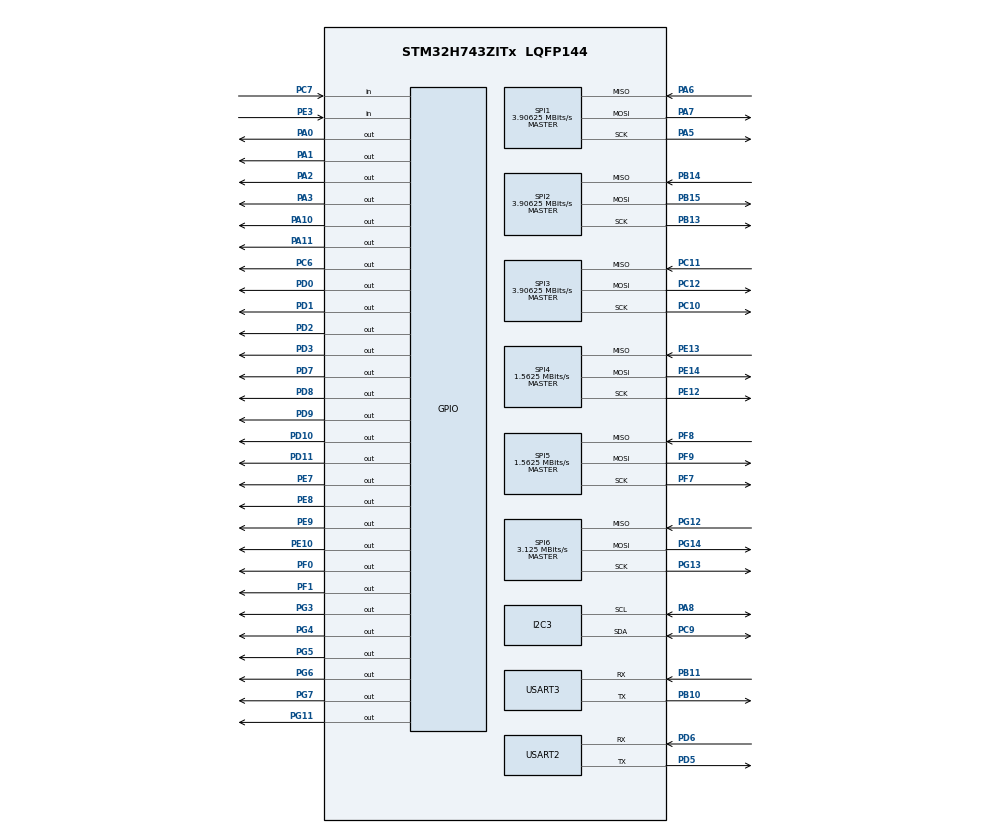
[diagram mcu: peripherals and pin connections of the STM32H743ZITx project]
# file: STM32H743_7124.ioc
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I2C3.Timing=0x00606092
Mcu.Family=STM32H7
Mcu.Name=STM32H743ZITx
Mcu.Package=LQFP144
NVIC.PriorityGroup=NVIC_PRIORITYGROUP_4
NVIC.TIM1_UP_IRQn=true\:0\:0\:false\:false\:true\:true\:true\:true
NVIC.TIM2_IRQn=true\:0\:0\:false\:false\:true\:true\:true\:true
NVIC.TIM3_IRQn=true\:0\:0\:false\:false\:true\:true\:true\:true
PA0.Signal=GPIO_Output
PA1.Signal=GPIO_Output
PA10.Signal=GPIO_Output
PA11.Signal=GPIO_Output
PA2.Signal=GPIO_Output
PA3.Signal=GPIO_Output
PA5.Mode=Full_Duplex_Master
PA5.Signal=SPI1_SCK
PA6.Mode=Full_Duplex_Master
PA6.Signal=SPI1_MISO
PA7.Mode=Full_Duplex_Master
PA7.Signal=SPI1_MOSI
PA8.Mode=I2C
PA8.Signal=I2C3_SCL
PB10.Mode=Asynchronous
PB10.Signal=USART3_TX
PB11.Mode=Asynchronous
PB11.Signal=USART3_RX
PB13.Mode=Full_Duplex_Master
PB13.Signal=SPI2_SCK
PB14.Mode=Full_Duplex_Master
PB14.Signal=SPI2_MISO
PB15.Mode=Full_Duplex_Master
PB15.Signal=SPI2_MOSI
PC10.Mode=Full_Duplex_Master
PC10.Signal=SPI3_SCK
PC11.Mode=Full_Duplex_Master
PC11.Signal=SPI3_MISO
PC12.Mode=Full_Duplex_Master
PC12.Signal=SPI3_MOSI
PC6.Signal=GPIO_Output
PC7.Signal=GPIO_Input
PC9.Mode=I2C
PC9.Signal=I2C3_SDA
PD0.Signal=GPIO_Output
PD1.Signal=GPIO_Output
PD10.Signal=GPIO_Output
PD11.Signal=GPIO_Output
PD2.Signal=GPIO_Output
PD3.Signal=GPIO_Output
PD5.Mode=Asynchronous
PD5.Signal=USART2_TX
PD6.Mode=Asynchronous
PD6.Signal=USART2_RX
PD7.Signal=GPIO_Output
PD8.Signal=GPIO_Output
PD9.Signal=GPIO_Output
PE10.Signal=GPIO_Output
PE12.Mode=Full_Duplex_Master
PE12.Signal=SPI4_SCK
PE13.Mode=Full_Duplex_Master
PE13.Signal=SPI4_MISO
PE14.Mode=Full_Duplex_Master
PE14.Signal=SPI4_MOSI
PE3.Signal=GPIO_Input
PE7.Signal=GPIO_Output
PE8.Signal=GPIO_Output
PE9.Signal=GPIO_Output
PF0.Signal=GPIO_Output
PF1.Signal=GPIO_Output
PF7.Mode=Full_Duplex_Master
PF7.Signal=SPI5_SCK
PF8.Mode=Full_Duplex_Master
PF8.Signal=SPI5_MISO
PF9.Mode=Full_Duplex_Master
PF9.Signal=SPI5_MOSI
PG11.Signal=GPIO_Output
PG12.Mode=Full_Duplex_Master
PG12.Signal=SPI6_MISO
PG13.Mode=Full_Duplex_Master
PG13.Signal=SPI6_SCK
PG14.Mode=Full_Duplex_Master
PG14.Signal=SPI6_MOSI
PG3.Signal=GPIO_Output
PG4.Signal=GPIO_Output
PG5.Signal=GPIO_Output
PG6.Signal=GPIO_Output
PG7.Signal=GPIO_Output
PH0-OSC_IN\ (PH0).Mode=HSE-External-Oscillator
PH0-OSC_IN\ (PH0).Signal=RCC_OSC_IN
PH1-OSC_OUT\ (PH1).Mode=HSE-External-Oscillator
PH1-OSC_OUT\ (PH1).Signal=RCC_OSC_OUT
ProjectManager.HeapSize=0x200
ProjectManager.StackSize=0x400
ProjectManager.TargetToolchain=MDK-ARM V5.27
RCC.ADCFreq_Value=62500000
RCC.APB1Freq_Value=25000000
RCC.APB2Freq_Value=25000000
RCC.APB3Freq_Value=50000000
RCC.APB4Freq_Value=50000000
RCC.CortexFreq_Value=400000000
RCC.D1PPRE=RCC_APB3_DIV2
RCC.D2PPRE1=RCC_APB1_DIV4
RCC.D2PPRE2=RCC_APB2_DIV4
RCC.D3PPRE=RCC_APB4_DIV2
RCC.DIVM1=2
RCC.DIVM2=2
RCC.DIVM3=2
RCC.DIVN1=64
RCC.DIVN2=50
RCC.DIVN3=50
RCC.DIVP2=10
RCC.HCLKFreq_Value=100000000
RCC.HPRE=RCC_HCLK_DIV4
RCC.HSE_VALUE=25000000
RCC.PLL1_VCI_Range-AdvancedSettings=RCC_PLL1VCIRANGE_1
RCC.PLL2_VCI_Range-AdvancedSettings=RCC_PLL2VCIRANGE_0
RCC.PLL2_VCO_SEL-AdvancedSettings=RCC_PLL2VCOMEDIUM
RCC.PLL3_VCI_Range-AdvancedSettings=RCC_PLL3VCIRANGE_0
RCC.PLLFRACN=0
RCC.PLLSourceVirtual=RCC_PLLSOURCE_HSE
RCC.SPI123CLockSelection=RCC_SPI123CLKSOURCE_PLL2
RCC.SYSCLKFreq_VALUE=400000000
RCC.SYSCLKSource=RCC_SYSCLKSOURCE_PLLCLK
RCC.USBFreq_Value=400000000
SPI1.BaudRatePrescaler=SPI_BAUDRATEPRESCALER_16
SPI1.CLKPhase=SPI_PHASE_2EDGE
SPI1.CLKPolarity=SPI_POLARITY_HIGH
SPI1.CalculateBaudRate=3.90625 MBits/s
SPI1.DataSize=SPI_DATASIZE_8BIT
SPI1.Direction=SPI_DIRECTION_2LINES
SPI1.Mode=SPI_MODE_MASTER
SPI1.NSSPMode=SPI_NSS_PULSE_DISABLE
SPI1.VirtualType=VM_MASTER
SPI2.BaudRatePrescaler=SPI_BAUDRATEPRESCALER_16
SPI2.CLKPhase=SPI_PHASE_2EDGE
SPI2.CLKPolarity=SPI_POLARITY_HIGH
SPI2.CalculateBaudRate=3.90625 MBits/s
SPI2.DataSize=SPI_DATASIZE_8BIT
SPI2.Direction=SPI_DIRECTION_2LINES
SPI2.Mode=SPI_MODE_MASTER
SPI2.NSSPMode=SPI_NSS_PULSE_DISABLE
SPI2.VirtualType=VM_MASTER
SPI3.BaudRatePrescaler=SPI_BAUDRATEPRESCALER_16
SPI3.CLKPhase=SPI_PHASE_2EDGE
SPI3.CLKPolarity=SPI_POLARITY_HIGH
SPI3.CalculateBaudRate=3.90625 MBits/s
SPI3.DataSize=SPI_DATASIZE_8BIT
SPI3.Direction=SPI_DIRECTION_2LINES
SPI3.Mode=SPI_MODE_MASTER
SPI3.NSSPMode=SPI_NSS_PULSE_DISABLE
SPI3.VirtualType=VM_MASTER
SPI4.BaudRatePrescaler=SPI_BAUDRATEPRESCALER_16
SPI4.CLKPhase=SPI_PHASE_2EDGE
SPI4.CLKPolarity=SPI_POLARITY_HIGH
SPI4.CalculateBaudRate=1.5625 MBits/s
SPI4.DataSize=SPI_DATASIZE_8BIT
SPI4.Direction=SPI_DIRECTION_2LINES
SPI4.Mode=SPI_MODE_MASTER
SPI4.NSSPMode=SPI_NSS_PULSE_DISABLE
SPI4.VirtualType=VM_MASTER
SPI5.BaudRatePrescaler=SPI_BAUDRATEPRESCALER_16
SPI5.CLKPhase=SPI_PHASE_2EDGE
SPI5.CLKPolarity=SPI_POLARITY_HIGH
SPI5.CalculateBaudRate=1.5625 MBits/s
SPI5.DataSize=SPI_DATASIZE_8BIT
SPI5.Direction=SPI_DIRECTION_2LINES
SPI5.Mode=SPI_MODE_MASTER
SPI5.NSSPMode=SPI_NSS_PULSE_DISABLE
SPI5.VirtualType=VM_MASTER
SPI6.BaudRatePrescaler=SPI_BAUDRATEPRESCALER_16
SPI6.CalculateBaudRate=3.125 MBits/s
SPI6.DataSize=SPI_DATASIZE_8BIT
SPI6.Direction=SPI_DIRECTION_2LINES
SPI6.Mode=SPI_MODE_MASTER
SPI6.NSSPMode=SPI_NSS_PULSE_DISABLE
SPI6.VirtualType=VM_MASTER
TIM1.Period=1000
TIM1.Prescaler=479
TIM2.Period=1000
TIM2.Prescaler=479
TIM3.Period=1000
TIM3.Prescaler=479
USART2.VirtualMode-Asynchronous=VM_ASYNC
USART3.VirtualMode-Asynchronous=VM_ASYNC
VP_TIM1_VS_ClockSourceINT.Mode=Internal
VP_TIM2_VS_ClockSourceINT.Mode=Internal
VP_TIM3_VS_ClockSourceINT.Mode=Internal
board=custom

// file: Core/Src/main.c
/* USER CODE BEGIN Header */
/**
  ******************************************************************************
  * @file           : main.c
  * @brief          : Main program body
  ******************************************************************************
  * @attention
  *
  * Copyright (c) 2022 STMicroelectronics.
  * All rights reserved.
  *
  * This software is licensed under terms that can be found in the LICENSE file
  * in the root directory of this software component.
  * If no LICENSE file comes with this software, it is provided AS-IS.
  *
  ******************************************************************************
  */
/* USER CODE END Header */
#include "main.h"

/* USER CODE BEGIN PM */
uint8_t TIMER_to_scan_Cnt;
uint8_t AD_scan_index=0;
int AD1_DATA[5],AD2_DATA[5],AD3_DATA[5],AD4_DATA[5],average_int=0;
/* USER CODE END PM */

I2C_HandleTypeDef hi2c3;

SPI_HandleTypeDef hspi1;
SPI_HandleTypeDef hspi2;
SPI_HandleTypeDef hspi3;
SPI_HandleTypeDef hspi4;
SPI_HandleTypeDef hspi5;
SPI_HandleTypeDef hspi6;

TIM_HandleTypeDef htim1;
TIM_HandleTypeDef htim2;
TIM_HandleTypeDef htim3;

UART_HandleTypeDef huart2;
UART_HandleTypeDef huart3;

/* USER CODE BEGIN PV */
AD7124REGSTRUCT   AD7124REG={0};
/* USER CODE END PV */

void SystemClock_Config(void);
void PeriphCommonClock_Config(void);
static void MX_GPIO_Init(void);
static void MX_I2C3_Init(void);
static void MX_SPI1_Init(void);
static void MX_SPI2_Init(void);
static void MX_SPI3_Init(void);
static void MX_SPI4_Init(void);
static void MX_SPI5_Init(void);
static void MX_SPI6_Init(void);
static void MX_TIM1_Init(void);
static void MX_TIM2_Init(void);
static void MX_TIM3_Init(void);
static void MX_USART2_UART_Init(void);
static void MX_USART3_UART_Init(void);

int main(void)
{
  /* USER CODE BEGIN 1 */
	uint8_t i;
  /* USER CODE END 1 */

  /* MCU Configuration--------------------------------------------------------*/

  /* Reset of all peripherals, Initializes the Flash interface and the Systick. */
  HAL_Init();

  /* Configure the system clock */
  SystemClock_Config();

/* Configure the peripherals common clocks */
  PeriphCommonClock_Config();

  /* Initialize all configured peripherals */
  MX_GPIO_Init();
  MX_I2C3_Init();
  MX_SPI1_Init();
  MX_SPI2_Init();
  MX_SPI3_Init();
  MX_SPI4_Init();
  MX_SPI5_Init();
  MX_SPI6_Init();
  MX_TIM1_Init();
  MX_TIM2_Init();
  MX_TIM3_Init();
  MX_USART2_UART_Init();
  MX_USART3_UART_Init();
  /* USER CODE BEGIN 2 */
	//for(i=0;i<4;i++)
	AD7124Init(&hspi1,0);
/*	AD7124Init(&hspi2);
	AD7124Init(&hspi3);
	AD7124Init(&hspi4);*/
  /* USER CODE END 2 */

  /* Infinite loop */
  while (1)
  {

    /* USER CODE BEGIN 3 */
		if(TIMER_to_scan_Cnt>100)
		{
			TIMER_to_scan_Cnt = 0;
			//scan_ad7124_channel(&hspi1,0,AD1_DATA);
			AD7124Init(&hspi1,0);
		}
  }
  /* USER CODE END 3 */
}

void SystemClock_Config(void)
{
  RCC_OscInitTypeDef RCC_OscInitStruct = {0};
  RCC_ClkInitTypeDef RCC_ClkInitStruct = {0};

  /** Supply configuration update enable
  */
  HAL_PWREx_ConfigSupply(PWR_LDO_SUPPLY);

  /** Configure the main internal regulator output voltage
  */
  __HAL_PWR_VOLTAGESCALING_CONFIG(PWR_REGULATOR_VOLTAGE_SCALE1);

  while(!__HAL_PWR_GET_FLAG(PWR_FLAG_VOSRDY)) {}

  __HAL_RCC_SYSCFG_CLK_ENABLE();
  __HAL_PWR_VOLTAGESCALING_CONFIG(PWR_REGULATOR_VOLTAGE_SCALE0);

  while(!__HAL_PWR_GET_FLAG(PWR_FLAG_VOSRDY)) {}

  /** Macro to configure the PLL clock source
  */
  __HAL_RCC_PLL_PLLSOURCE_CONFIG(RCC_PLLSOURCE_HSE);

  /** Initializes the RCC Oscillators according to the specified parameters
  * in the RCC_OscInitTypeDef structure.
  */
  RCC_OscInitStruct.OscillatorType = RCC_OSCILLATORTYPE_HSE;
  RCC_OscInitStruct.HSEState = RCC_HSE_ON;
  RCC_OscInitStruct.PLL.PLLState = RCC_PLL_ON;
  RCC_OscInitStruct.PLL.PLLSource = RCC_PLLSOURCE_HSE;
  RCC_OscInitStruct.PLL.PLLM = 2;
  RCC_OscInitStruct.PLL.PLLN = 240;
  RCC_OscInitStruct.PLL.PLLP = 2;
  RCC_OscInitStruct.PLL.PLLQ = 2;
  RCC_OscInitStruct.PLL.PLLR = 2;
  RCC_OscInitStruct.PLL.PLLRGE = RCC_PLL1VCIRANGE_2;
  RCC_OscInitStruct.PLL.PLLVCOSEL = RCC_PLL1VCOWIDE;
  RCC_OscInitStruct.PLL.PLLFRACN = 0;
  if (HAL_RCC_OscConfig(&RCC_OscInitStruct) != HAL_OK)
  {
    Error_Handler();
  }

  /** Initializes the CPU, AHB and APB buses clocks
  */
  RCC_ClkInitStruct.ClockType = RCC_CLOCKTYPE_HCLK|RCC_CLOCKTYPE_SYSCLK
                              |RCC_CLOCKTYPE_PCLK1|RCC_CLOCKTYPE_PCLK2
                              |RCC_CLOCKTYPE_D3PCLK1|RCC_CLOCKTYPE_D1PCLK1;
  RCC_ClkInitStruct.SYSCLKSource = RCC_SYSCLKSOURCE_PLLCLK;
  RCC_ClkInitStruct.SYSCLKDivider = RCC_SYSCLK_DIV1;
  RCC_ClkInitStruct.AHBCLKDivider = RCC_HCLK_DIV4;
  RCC_ClkInitStruct.APB3CLKDivider = RCC_APB3_DIV2;
  RCC_ClkInitStruct.APB1CLKDivider = RCC_APB1_DIV4;
  RCC_ClkInitStruct.APB2CLKDivider = RCC_APB2_DIV4;
  RCC_ClkInitStruct.APB4CLKDivider = RCC_APB4_DIV2;

  if (HAL_RCC_ClockConfig(&RCC_ClkInitStruct, FLASH_LATENCY_1) != HAL_OK)
  {
    Error_Handler();
  }
}

void PeriphCommonClock_Config(void)
{
  RCC_PeriphCLKInitTypeDef PeriphClkInitStruct = {0};

  /** Initializes the peripherals clock
  */
  PeriphClkInitStruct.PeriphClockSelection = RCC_PERIPHCLK_SPI3|RCC_PERIPHCLK_SPI2
                              |RCC_PERIPHCLK_SPI1;
  PeriphClkInitStruct.PLL2.PLL2M = 2;
  PeriphClkInitStruct.PLL2.PLL2N = 50;
  PeriphClkInitStruct.PLL2.PLL2P = 10;
  PeriphClkInitStruct.PLL2.PLL2Q = 2;
  PeriphClkInitStruct.PLL2.PLL2R = 2;
  PeriphClkInitStruct.PLL2.PLL2RGE = RCC_PLL2VCIRANGE_2;
  PeriphClkInitStruct.PLL2.PLL2VCOSEL = RCC_PLL2VCOMEDIUM;
  PeriphClkInitStruct.PLL2.PLL2FRACN = 0;
  PeriphClkInitStruct.Spi123ClockSelection = RCC_SPI123CLKSOURCE_PLL2;
  if (HAL_RCCEx_PeriphCLKConfig(&PeriphClkInitStruct) != HAL_OK)
  {
    Error_Handler();
  }
}

static void MX_I2C3_Init(void)
{

  hi2c3.Instance = I2C3;
  hi2c3.Init.Timing = 0x007074AF;
  hi2c3.Init.OwnAddress1 = 0;
  hi2c3.Init.AddressingMode = I2C_ADDRESSINGMODE_7BIT;
  hi2c3.Init.DualAddressMode = I2C_DUALADDRESS_DISABLE;
  hi2c3.Init.OwnAddress2 = 0;
  hi2c3.Init.OwnAddress2Masks = I2C_OA2_NOMASK;
  hi2c3.Init.GeneralCallMode = I2C_GENERALCALL_DISABLE;
  hi2c3.Init.NoStretchMode = I2C_NOSTRETCH_DISABLE;
  if (HAL_I2C_Init(&hi2c3) != HAL_OK)
  {
    Error_Handler();
  }

  /** Configure Analogue filter
  */
  if (HAL_I2CEx_ConfigAnalogFilter(&hi2c3, I2C_ANALOGFILTER_ENABLE) != HAL_OK)
  {
    Error_Handler();
  }

  /** Configure Digital filter
  */
  if (HAL_I2CEx_ConfigDigitalFilter(&hi2c3, 0) != HAL_OK)
  {
    Error_Handler();
  }

}

static void MX_SPI1_Init(void)
{

  /* SPI1 parameter configuration*/
  hspi1.Instance = SPI1;
  hspi1.Init.Mode = SPI_MODE_MASTER;
  hspi1.Init.Direction = SPI_DIRECTION_2LINES;
  hspi1.Init.DataSize = SPI_DATASIZE_8BIT;
  hspi1.Init.CLKPolarity = SPI_POLARITY_HIGH;
  hspi1.Init.CLKPhase = SPI_PHASE_2EDGE;
  hspi1.Init.NSS = SPI_NSS_SOFT;
  hspi1.Init.BaudRatePrescaler = SPI_BAUDRATEPRESCALER_128;
  hspi1.Init.FirstBit = SPI_FIRSTBIT_MSB;
  hspi1.Init.TIMode = SPI_TIMODE_DISABLE;
  hspi1.Init.CRCCalculation = SPI_CRCCALCULATION_DISABLE;
  hspi1.Init.CRCPolynomial = 10;
  hspi1.Init.NSSPMode = SPI_NSS_PULSE_DISABLE;
  hspi1.Init.NSSPolarity = SPI_NSS_POLARITY_LOW;
  hspi1.Init.FifoThreshold = SPI_FIFO_THRESHOLD_01DATA;
  hspi1.Init.TxCRCInitializationPattern = SPI_CRC_INITIALIZATION_ALL_ZERO_PATTERN;
  hspi1.Init.RxCRCInitializationPattern = SPI_CRC_INITIALIZATION_ALL_ZERO_PATTERN;
  hspi1.Init.MasterSSIdleness = SPI_MASTER_SS_IDLENESS_00CYCLE;
  hspi1.Init.MasterInterDataIdleness = SPI_MASTER_INTERDATA_IDLENESS_00CYCLE;
  hspi1.Init.MasterReceiverAutoSusp = SPI_MASTER_RX_AUTOSUSP_DISABLE;
  hspi1.Init.MasterKeepIOState = SPI_MASTER_KEEP_IO_STATE_DISABLE;
  hspi1.Init.IOSwap = SPI_IO_SWAP_DISABLE;
  if (HAL_SPI_Init(&hspi1) != HAL_OK)
  {
    Error_Handler();
  }

}

static void MX_SPI2_Init(void)
{

  /* SPI2 parameter configuration*/
  hspi2.Instance = SPI2;
  hspi2.Init.Mode = SPI_MODE_MASTER;
  hspi2.Init.Direction = SPI_DIRECTION_2LINES;
  hspi2.Init.DataSize = SPI_DATASIZE_8BIT;
  hspi2.Init.CLKPolarity = SPI_POLARITY_HIGH;
  hspi2.Init.CLKPhase = SPI_PHASE_2EDGE;
  hspi2.Init.NSS = SPI_NSS_SOFT;
  hspi2.Init.BaudRatePrescaler = SPI_BAUDRATEPRESCALER_16;
  hspi2.Init.FirstBit = SPI_FIRSTBIT_MSB;
  hspi2.Init.TIMode = SPI_TIMODE_DISABLE;
  hspi2.Init.CRCCalculation = SPI_CRCCALCULATION_DISABLE;
  hspi2.Init.CRCPolynomial = 0x0;
  hspi2.Init.NSSPMode = SPI_NSS_PULSE_DISABLE;
  hspi2.Init.NSSPolarity = SPI_NSS_POLARITY_LOW;
  hspi2.Init.FifoThreshold = SPI_FIFO_THRESHOLD_01DATA;
  hspi2.Init.TxCRCInitializationPattern = SPI_CRC_INITIALIZATION_ALL_ZERO_PATTERN;
  hspi2.Init.RxCRCInitializationPattern = SPI_CRC_INITIALIZATION_ALL_ZERO_PATTERN;
  hspi2.Init.MasterSSIdleness = SPI_MASTER_SS_IDLENESS_00CYCLE;
  hspi2.Init.MasterInterDataIdleness = SPI_MASTER_INTERDATA_IDLENESS_00CYCLE;
  hspi2.Init.MasterReceiverAutoSusp = SPI_MASTER_RX_AUTOSUSP_DISABLE;
  hspi2.Init.MasterKeepIOState = SPI_MASTER_KEEP_IO_STATE_DISABLE;
  hspi2.Init.IOSwap = SPI_IO_SWAP_DISABLE;
  if (HAL_SPI_Init(&hspi2) != HAL_OK)
  {
    Error_Handler();
  }

}

static void MX_SPI3_Init(void)
{

  /* SPI3 parameter configuration*/
  hspi3.Instance = SPI3;
  hspi3.Init.Mode = SPI_MODE_MASTER;
  hspi3.Init.Direction = SPI_DIRECTION_2LINES;
  hspi3.Init.DataSize = SPI_DATASIZE_8BIT;
  hspi3.Init.CLKPolarity = SPI_POLARITY_HIGH;
  hspi3.Init.CLKPhase = SPI_PHASE_2EDGE;
  hspi3.Init.NSS = SPI_NSS_SOFT;
  hspi3.Init.BaudRatePrescaler = SPI_BAUDRATEPRESCALER_16;
  hspi3.Init.FirstBit = SPI_FIRSTBIT_MSB;
  hspi3.Init.TIMode = SPI_TIMODE_DISABLE;
  hspi3.Init.CRCCalculation = SPI_CRCCALCULATION_DISABLE;
  hspi3.Init.CRCPolynomial = 0x0;
  hspi3.Init.NSSPMode = SPI_NSS_PULSE_DISABLE;
  hspi3.Init.NSSPolarity = SPI_NSS_POLARITY_LOW;
  hspi3.Init.FifoThreshold = SPI_FIFO_THRESHOLD_01DATA;
  hspi3.Init.TxCRCInitializationPattern = SPI_CRC_INITIALIZATION_ALL_ZERO_PATTERN;
  hspi3.Init.RxCRCInitializationPattern = SPI_CRC_INITIALIZATION_ALL_ZERO_PATTERN;
  hspi3.Init.MasterSSIdleness = SPI_MASTER_SS_IDLENESS_00CYCLE;
  hspi3.Init.MasterInterDataIdleness = SPI_MASTER_INTERDATA_IDLENESS_00CYCLE;
  hspi3.Init.MasterReceiverAutoSusp = SPI_MASTER_RX_AUTOSUSP_DISABLE;
  hspi3.Init.MasterKeepIOState = SPI_MASTER_KEEP_IO_STATE_DISABLE;
  hspi3.Init.IOSwap = SPI_IO_SWAP_DISABLE;
  if (HAL_SPI_Init(&hspi3) != HAL_OK)
  {
    Error_Handler();
  }

}

static void MX_SPI4_Init(void)
{

  /* SPI4 parameter configuration*/
  hspi4.Instance = SPI4;
  hspi4.Init.Mode = SPI_MODE_MASTER;
  hspi4.Init.Direction = SPI_DIRECTION_2LINES;
  hspi4.Init.DataSize = SPI_DATASIZE_8BIT;
  hspi4.Init.CLKPolarity = SPI_POLARITY_HIGH;
  hspi4.Init.CLKPhase = SPI_PHASE_2EDGE;
  hspi4.Init.NSS = SPI_NSS_SOFT;
  hspi4.Init.BaudRatePrescaler = SPI_BAUDRATEPRESCALER_16;
  hspi4.Init.FirstBit = SPI_FIRSTBIT_MSB;
  hspi4.Init.TIMode = SPI_TIMODE_DISABLE;
  hspi4.Init.CRCCalculation = SPI_CRCCALCULATION_DISABLE;
  hspi4.Init.CRCPolynomial = 0x0;
  hspi4.Init.NSSPMode = SPI_NSS_PULSE_DISABLE;
  hspi4.Init.NSSPolarity = SPI_NSS_POLARITY_LOW;
  hspi4.Init.FifoThreshold = SPI_FIFO_THRESHOLD_01DATA;
  hspi4.Init.TxCRCInitializationPattern = SPI_CRC_INITIALIZATION_ALL_ZERO_PATTERN;
  hspi4.Init.RxCRCInitializationPattern = SPI_CRC_INITIALIZATION_ALL_ZERO_PATTERN;
  hspi4.Init.MasterSSIdleness = SPI_MASTER_SS_IDLENESS_00CYCLE;
  hspi4.Init.MasterInterDataIdleness = SPI_MASTER_INTERDATA_IDLENESS_00CYCLE;
  hspi4.Init.MasterReceiverAutoSusp = SPI_MASTER_RX_AUTOSUSP_DISABLE;
  hspi4.Init.MasterKeepIOState = SPI_MASTER_KEEP_IO_STATE_DISABLE;
  hspi4.Init.IOSwap = SPI_IO_SWAP_DISABLE;
  if (HAL_SPI_Init(&hspi4) != HAL_OK)
  {
    Error_Handler();
  }

}

static void MX_SPI5_Init(void)
{

  /* SPI5 parameter configuration*/
  hspi5.Instance = SPI5;
  hspi5.Init.Mode = SPI_MODE_MASTER;
  hspi5.Init.Direction = SPI_DIRECTION_2LINES;
  hspi5.Init.DataSize = SPI_DATASIZE_8BIT;
  hspi5.Init.CLKPolarity = SPI_POLARITY_HIGH;
  hspi5.Init.CLKPhase = SPI_PHASE_2EDGE;
  hspi5.Init.NSS = SPI_NSS_SOFT;
  hspi5.Init.BaudRatePrescaler = SPI_BAUDRATEPRESCALER_16;
  hspi5.Init.FirstBit = SPI_FIRSTBIT_MSB;
  hspi5.Init.TIMode = SPI_TIMODE_DISABLE;
  hspi5.Init.CRCCalculation = SPI_CRCCALCULATION_DISABLE;
  hspi5.Init.CRCPolynomial = 0x0;
  hspi5.Init.NSSPMode = SPI_NSS_PULSE_DISABLE;
  hspi5.Init.NSSPolarity = SPI_NSS_POLARITY_LOW;
  hspi5.Init.FifoThreshold = SPI_FIFO_THRESHOLD_01DATA;
  hspi5.Init.TxCRCInitializationPattern = SPI_CRC_INITIALIZATION_ALL_ZERO_PATTERN;
  hspi5.Init.RxCRCInitializationPattern = SPI_CRC_INITIALIZATION_ALL_ZERO_PATTERN;
  hspi5.Init.MasterSSIdleness = SPI_MASTER_SS_IDLENESS_00CYCLE;
  hspi5.Init.MasterInterDataIdleness = SPI_MASTER_INTERDATA_IDLENESS_00CYCLE;
  hspi5.Init.MasterReceiverAutoSusp = SPI_MASTER_RX_AUTOSUSP_DISABLE;
  hspi5.Init.MasterKeepIOState = SPI_MASTER_KEEP_IO_STATE_DISABLE;
  hspi5.Init.IOSwap = SPI_IO_SWAP_DISABLE;
  if (HAL_SPI_Init(&hspi5) != HAL_OK)
  {
    Error_Handler();
  }

}

static void MX_SPI6_Init(void)
{

  /* SPI6 parameter configuration*/
  hspi6.Instance = SPI6;
  hspi6.Init.Mode = SPI_MODE_MASTER;
  hspi6.Init.Direction = SPI_DIRECTION_2LINES;
  hspi6.Init.DataSize = SPI_DATASIZE_8BIT;
  hspi6.Init.CLKPolarity = SPI_POLARITY_LOW;
  hspi6.Init.CLKPhase = SPI_PHASE_1EDGE;
  hspi6.Init.NSS = SPI_NSS_SOFT;
  hspi6.Init.BaudRatePrescaler = SPI_BAUDRATEPRESCALER_16;
  hspi6.Init.FirstBit = SPI_FIRSTBIT_MSB;
  hspi6.Init.TIMode = SPI_TIMODE_DISABLE;
  hspi6.Init.CRCCalculation = SPI_CRCCALCULATION_DISABLE;
  hspi6.Init.CRCPolynomial = 0x0;
  hspi6.Init.NSSPMode = SPI_NSS_PULSE_DISABLE;
  hspi6.Init.NSSPolarity = SPI_NSS_POLARITY_LOW;
  hspi6.Init.FifoThreshold = SPI_FIFO_THRESHOLD_01DATA;
  hspi6.Init.TxCRCInitializationPattern = SPI_CRC_INITIALIZATION_ALL_ZERO_PATTERN;
  hspi6.Init.RxCRCInitializationPattern = SPI_CRC_INITIALIZATION_ALL_ZERO_PATTERN;
  hspi6.Init.MasterSSIdleness = SPI_MASTER_SS_IDLENESS_00CYCLE;
  hspi6.Init.MasterInterDataIdleness = SPI_MASTER_INTERDATA_IDLENESS_00CYCLE;
  hspi6.Init.MasterReceiverAutoSusp = SPI_MASTER_RX_AUTOSUSP_DISABLE;
  hspi6.Init.MasterKeepIOState = SPI_MASTER_KEEP_IO_STATE_DISABLE;
  hspi6.Init.IOSwap = SPI_IO_SWAP_DISABLE;
  if (HAL_SPI_Init(&hspi6) != HAL_OK)
  {
    Error_Handler();
  }

}

static void MX_TIM1_Init(void)
{

  TIM_ClockConfigTypeDef sClockSourceConfig = {0};
  TIM_MasterConfigTypeDef sMasterConfig = {0};

  htim1.Instance = TIM1;
  htim1.Init.Prescaler = 479;
  htim1.Init.CounterMode = TIM_COUNTERMODE_UP;
  htim1.Init.Period = 1000;
  htim1.Init.ClockDivision = TIM_CLOCKDIVISION_DIV1;
  htim1.Init.RepetitionCounter = 0;
  htim1.Init.AutoReloadPreload = TIM_AUTORELOAD_PRELOAD_DISABLE;
  if (HAL_TIM_Base_Init(&htim1) != HAL_OK)
  {
    Error_Handler();
  }
  sClockSourceConfig.ClockSource = TIM_CLOCKSOURCE_INTERNAL;
  if (HAL_TIM_ConfigClockSource(&htim1, &sClockSourceConfig) != HAL_OK)
  {
    Error_Handler();
  }
  sMasterConfig.MasterOutputTrigger = TIM_TRGO_RESET;
  sMasterConfig.MasterOutputTrigger2 = TIM_TRGO2_RESET;
  sMasterConfig.MasterSlaveMode = TIM_MASTERSLAVEMODE_DISABLE;
  if (HAL_TIMEx_MasterConfigSynchronization(&htim1, &sMasterConfig) != HAL_OK)
  {
    Error_Handler();
  }
  /* USER CODE BEGIN TIM1_Init 2 */
	HAL_TIM_Base_Start_IT(&htim1);
  /* USER CODE END TIM1_Init 2 */

}

static void MX_TIM2_Init(void)
{

  TIM_ClockConfigTypeDef sClockSourceConfig = {0};
  TIM_MasterConfigTypeDef sMasterConfig = {0};

  htim2.Instance = TIM2;
  htim2.Init.Prescaler = 479;
  htim2.Init.CounterMode = TIM_COUNTERMODE_UP;
  htim2.Init.Period = 1000;
  htim2.Init.ClockDivision = TIM_CLOCKDIVISION_DIV1;
  htim2.Init.AutoReloadPreload = TIM_AUTORELOAD_PRELOAD_DISABLE;
  if (HAL_TIM_Base_Init(&htim2) != HAL_OK)
  {
    Error_Handler();
  }
  sClockSourceConfig.ClockSource = TIM_CLOCKSOURCE_INTERNAL;
  if (HAL_TIM_ConfigClockSource(&htim2, &sClockSourceConfig) != HAL_OK)
  {
    Error_Handler();
  }
  sMasterConfig.MasterOutputTrigger = TIM_TRGO_RESET;
  sMasterConfig.MasterSlaveMode = TIM_MASTERSLAVEMODE_DISABLE;
  if (HAL_TIMEx_MasterConfigSynchronization(&htim2, &sMasterConfig) != HAL_OK)
  {
    Error_Handler();
  }
  /* USER CODE BEGIN TIM2_Init 2 */
	HAL_TIM_Base_Start_IT(&htim2);
  /* USER CODE END TIM2_Init 2 */

}

static void MX_TIM3_Init(void)
{

  TIM_ClockConfigTypeDef sClockSourceConfig = {0};
  TIM_MasterConfigTypeDef sMasterConfig = {0};

  htim3.Instance = TIM3;
  htim3.Init.Prescaler = 479;
  htim3.Init.CounterMode = TIM_COUNTERMODE_UP;
  htim3.Init.Period = 1000;
  htim3.Init.ClockDivision = TIM_CLOCKDIVISION_DIV1;
  htim3.Init.AutoReloadPreload = TIM_AUTORELOAD_PRELOAD_DISABLE;
  if (HAL_TIM_Base_Init(&htim3) != HAL_OK)
  {
    Error_Handler();
  }
  sClockSourceConfig.ClockSource = TIM_CLOCKSOURCE_INTERNAL;
  if (HAL_TIM_ConfigClockSource(&htim3, &sClockSourceConfig) != HAL_OK)
  {
    Error_Handler();
  }
  sMasterConfig.MasterOutputTrigger = TIM_TRGO_RESET;
  sMasterConfig.MasterSlaveMode = TIM_MASTERSLAVEMODE_DISABLE;
  if (HAL_TIMEx_MasterConfigSynchronization(&htim3, &sMasterConfig) != HAL_OK)
  {
    Error_Handler();
  }
  /* USER CODE BEGIN TIM3_Init 2 */
	HAL_TIM_Base_Start_IT(&htim3);
  /* USER CODE END TIM3_Init 2 */

}

static void MX_USART2_UART_Init(void)
{

  huart2.Instance = USART2;
  huart2.Init.BaudRate = 115200;
  huart2.Init.WordLength = UART_WORDLENGTH_8B;
  huart2.Init.StopBits = UART_STOPBITS_1;
  huart2.Init.Parity = UART_PARITY_NONE;
  huart2.Init.Mode = UART_MODE_TX_RX;
  huart2.Init.HwFlowCtl = UART_HWCONTROL_NONE;
  huart2.Init.OverSampling = UART_OVERSAMPLING_16;
  huart2.Init.OneBitSampling = UART_ONE_BIT_SAMPLE_DISABLE;
  huart2.Init.ClockPrescaler = UART_PRESCALER_DIV1;
  huart2.AdvancedInit.AdvFeatureInit = UART_ADVFEATURE_NO_INIT;
  if (HAL_UART_Init(&huart2) != HAL_OK)
  {
    Error_Handler();
  }
  if (HAL_UARTEx_SetTxFifoThreshold(&huart2, UART_TXFIFO_THRESHOLD_1_8) != HAL_OK)
  {
    Error_Handler();
  }
  if (HAL_UARTEx_SetRxFifoThreshold(&huart2, UART_RXFIFO_THRESHOLD_1_8) != HAL_OK)
  {
    Error_Handler();
  }
  if (HAL_UARTEx_DisableFifoMode(&huart2) != HAL_OK)
  {
    Error_Handler();
  }

}

static void MX_USART3_UART_Init(void)
{

  huart3.Instance = USART3;
  huart3.Init.BaudRate = 115200;
  huart3.Init.WordLength = UART_WORDLENGTH_8B;
  huart3.Init.StopBits = UART_STOPBITS_1;
  huart3.Init.Parity = UART_PARITY_NONE;
  huart3.Init.Mode = UART_MODE_TX_RX;
  huart3.Init.HwFlowCtl = UART_HWCONTROL_NONE;
  huart3.Init.OverSampling = UART_OVERSAMPLING_16;
  huart3.Init.OneBitSampling = UART_ONE_BIT_SAMPLE_DISABLE;
  huart3.Init.ClockPrescaler = UART_PRESCALER_DIV1;
  huart3.AdvancedInit.AdvFeatureInit = UART_ADVFEATURE_NO_INIT;
  if (HAL_UART_Init(&huart3) != HAL_OK)
  {
    Error_Handler();
  }
  if (HAL_UARTEx_SetTxFifoThreshold(&huart3, UART_TXFIFO_THRESHOLD_1_8) != HAL_OK)
  {
    Error_Handler();
  }
  if (HAL_UARTEx_SetRxFifoThreshold(&huart3, UART_RXFIFO_THRESHOLD_1_8) != HAL_OK)
  {
    Error_Handler();
  }
  if (HAL_UARTEx_DisableFifoMode(&huart3) != HAL_OK)
  {
    Error_Handler();
  }

}

static void MX_GPIO_Init(void)
{
  GPIO_InitTypeDef GPIO_InitStruct = {0};

  /* GPIO Ports Clock Enable */
  __HAL_RCC_GPIOE_CLK_ENABLE();
  __HAL_RCC_GPIOF_CLK_ENABLE();
  __HAL_RCC_GPIOH_CLK_ENABLE();
  __HAL_RCC_GPIOA_CLK_ENABLE();
  __HAL_RCC_GPIOB_CLK_ENABLE();
  __HAL_RCC_GPIOD_CLK_ENABLE();
  __HAL_RCC_GPIOG_CLK_ENABLE();
  __HAL_RCC_GPIOC_CLK_ENABLE();

  /*Configure GPIO pin Output Level */
  HAL_GPIO_WritePin(GPIOF, GPIO_PIN_0|GPIO_PIN_1, GPIO_PIN_RESET);

  /*Configure GPIO pin Output Level */
  HAL_GPIO_WritePin(GPIOA, GPIO_PIN_0|GPIO_PIN_1|GPIO_PIN_2|GPIO_PIN_3
                          |GPIO_PIN_10|GPIO_PIN_11, GPIO_PIN_RESET);

  /*Configure GPIO pin Output Level */
  HAL_GPIO_WritePin(GPIOE, GPIO_PIN_7|GPIO_PIN_8|GPIO_PIN_9|GPIO_PIN_10, GPIO_PIN_RESET);

  /*Configure GPIO pin Output Level */
  HAL_GPIO_WritePin(GPIOD, GPIO_PIN_8|GPIO_PIN_9|GPIO_PIN_10|GPIO_PIN_11
                          |GPIO_PIN_0|GPIO_PIN_1|GPIO_PIN_2|GPIO_PIN_3
                          |GPIO_PIN_7, GPIO_PIN_RESET);

  /*Configure GPIO pin Output Level */
  HAL_GPIO_WritePin(GPIOG, GPIO_PIN_3|GPIO_PIN_4|GPIO_PIN_5|GPIO_PIN_6
                          |GPIO_PIN_7|GPIO_PIN_11, GPIO_PIN_RESET);

  /*Configure GPIO pin Output Level */
  HAL_GPIO_WritePin(GPIOC, GPIO_PIN_6, GPIO_PIN_RESET);

  /*Configure GPIO pin : PE3 */
  GPIO_InitStruct.Pin = GPIO_PIN_3;
  GPIO_InitStruct.Mode = GPIO_MODE_INPUT;
  GPIO_InitStruct.Pull = GPIO_NOPULL;
  HAL_GPIO_Init(GPIOE, &GPIO_InitStruct);

  /*Configure GPIO pins : PF0 PF1 */
  GPIO_InitStruct.Pin = GPIO_PIN_0|GPIO_PIN_1;
  GPIO_InitStruct.Mode = GPIO_MODE_OUTPUT_PP;
  GPIO_InitStruct.Pull = GPIO_NOPULL;
  GPIO_InitStruct.Speed = GPIO_SPEED_FREQ_LOW;
  HAL_GPIO_Init(GPIOF, &GPIO_InitStruct);

  /*Configure GPIO pins : PA0 PA1 PA2 PA3
                           PA10 PA11 */
  GPIO_InitStruct.Pin = GPIO_PIN_0|GPIO_PIN_1|GPIO_PIN_2|GPIO_PIN_3
                          |GPIO_PIN_10|GPIO_PIN_11;
  GPIO_InitStruct.Mode = GPIO_MODE_OUTPUT_PP;
  GPIO_InitStruct.Pull = GPIO_NOPULL;
  GPIO_InitStruct.Speed = GPIO_SPEED_FREQ_LOW;
  HAL_GPIO_Init(GPIOA, &GPIO_InitStruct);

  /*Configure GPIO pins : PE7 PE8 PE9 PE10 */
  GPIO_InitStruct.Pin = GPIO_PIN_7|GPIO_PIN_8|GPIO_PIN_9|GPIO_PIN_10;
  GPIO_InitStruct.Mode = GPIO_MODE_OUTPUT_PP;
  GPIO_InitStruct.Pull = GPIO_NOPULL;
  GPIO_InitStruct.Speed = GPIO_SPEED_FREQ_LOW;
  HAL_GPIO_Init(GPIOE, &GPIO_InitStruct);

  /*Configure GPIO pins : PD8 PD9 PD10 PD11
                           PD0 PD1 PD2 PD3
                           PD7 */
  GPIO_InitStruct.Pin = GPIO_PIN_8|GPIO_PIN_9|GPIO_PIN_10|GPIO_PIN_11
                          |GPIO_PIN_0|GPIO_PIN_1|GPIO_PIN_2|GPIO_PIN_3
                          |GPIO_PIN_7;
  GPIO_InitStruct.Mode = GPIO_MODE_OUTPUT_PP;
  GPIO_InitStruct.Pull = GPIO_NOPULL;
  GPIO_InitStruct.Speed = GPIO_SPEED_FREQ_LOW;
  HAL_GPIO_Init(GPIOD, &GPIO_InitStruct);

  /*Configure GPIO pins : PG3 PG4 PG5 PG6
                           PG7 PG11 */
  GPIO_InitStruct.Pin = GPIO_PIN_3|GPIO_PIN_4|GPIO_PIN_5|GPIO_PIN_6
                          |GPIO_PIN_7|GPIO_PIN_11;
  GPIO_InitStruct.Mode = GPIO_MODE_OUTPUT_PP;
  GPIO_InitStruct.Pull = GPIO_NOPULL;
  GPIO_InitStruct.Speed = GPIO_SPEED_FREQ_LOW;
  HAL_GPIO_Init(GPIOG, &GPIO_InitStruct);

  /*Configure GPIO pin : PC6 */
  GPIO_InitStruct.Pin = GPIO_PIN_6;
  GPIO_InitStruct.Mode = GPIO_MODE_OUTPUT_PP;
  GPIO_InitStruct.Pull = GPIO_NOPULL;
  GPIO_InitStruct.Speed = GPIO_SPEED_FREQ_LOW;
  HAL_GPIO_Init(GPIOC, &GPIO_InitStruct);

  /*Configure GPIO pin : PC7 */
  GPIO_InitStruct.Pin = GPIO_PIN_7;
  GPIO_InitStruct.Mode = GPIO_MODE_INPUT;
  GPIO_InitStruct.Pull = GPIO_NOPULL;
  HAL_GPIO_Init(GPIOC, &GPIO_InitStruct);

}

void Error_Handler(void)
{
  __disable_irq();
  while (1)
  {
  }
}
